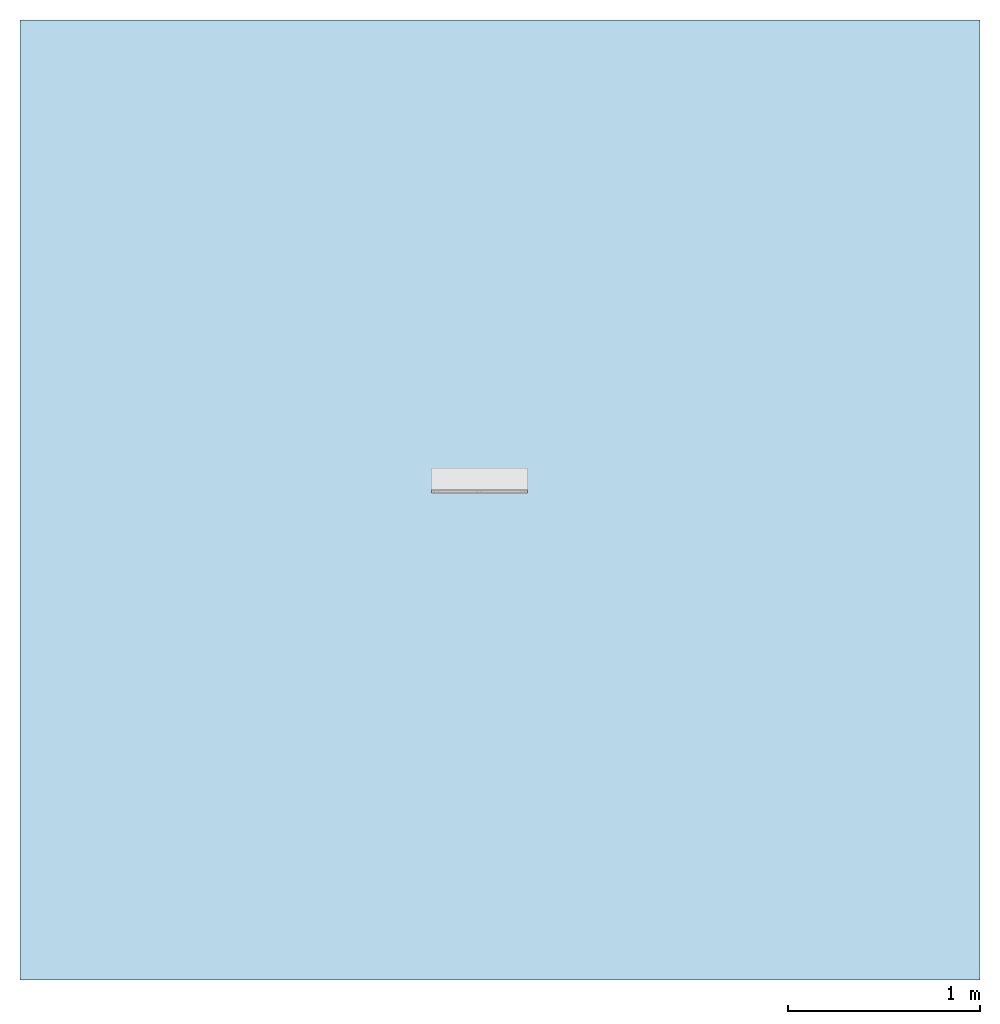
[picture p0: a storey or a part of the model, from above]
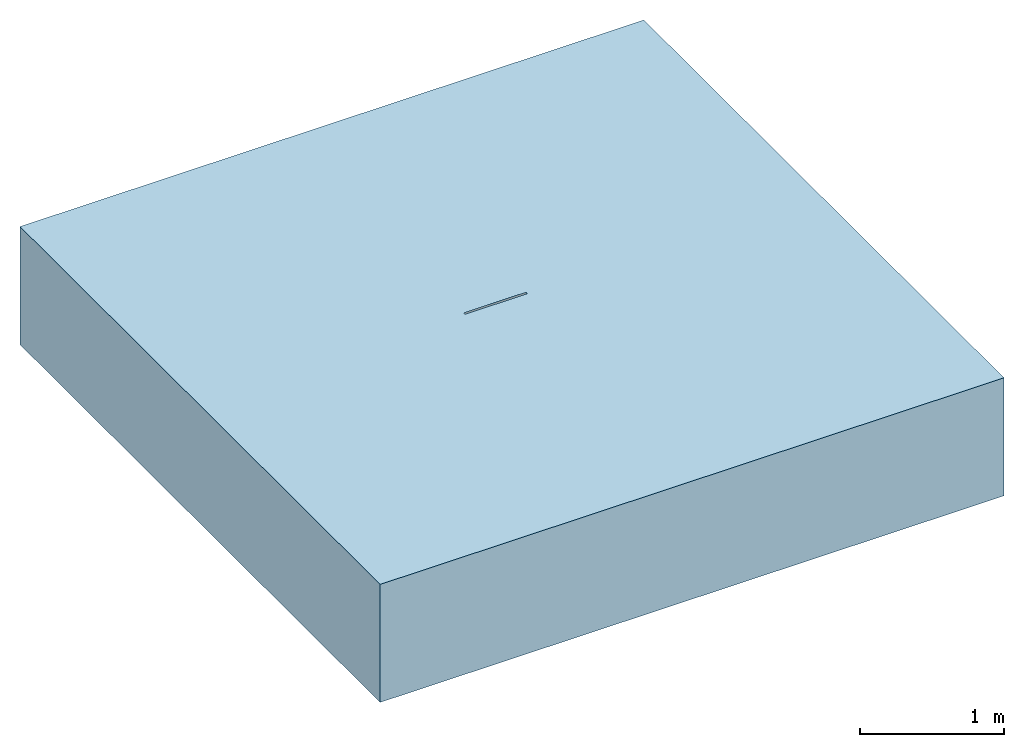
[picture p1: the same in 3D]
Properties of the parts of a building model (IFC2X3)

# File
Description: ViewDefinition [CoordinationView]
File name: 23301 - No 30.1J Constant Depth Channel - 500mm LG - Invert Depth 280mm.ifc
Time: 2013-10-31T17:35:21
Written by: Autodesk Revit 2013
Made in: 20120221_2030(x64)

# IfcProject, Project Number
LongName: Project Name; Phase: Project Status

# IfcSite, Default
RefLatitude: 42, 21, 30, 344238; RefLongitude: -71, -3, -35, -194702; RefElevation: 0 mm

# IfcBuilding
Pset_BuildingCommon - NumberOfStoreys: 1
Other - Client Name: Owner; Project Issue Date: Issue Date; Project Name: Project Name; Project Address: ## Street City, State Zip; Project Status: Project Status; Project Number: Project Number

# IfcBuildingStorey, Level 1
LongName: Level 1; Elevation: 0 mm
Constraints - Elevation Base: 0; Elevation: 0 mm
Graphics - Symbol: M_Level Head - Circle: M_Level Head - Circle; Symbol at End 2 Default: yes; Symbol at End 1 Default: no; Line Pattern: Center; Line Weight: 1; Color: 0
Identity Data - Building Story: yes; Name: Level 1; Structural: no
Dimensions - Computation Height: 0 mm

# IfcBuildingElementProxy: 23301 - No 30.1J Constant Depth Channel - 500mm LG - Invert Depth 280mm, Civil-Drainage-Channel-ACO-MultiDrain-M100D-Brickslot-Channel-System:23301 - No 30.1J Constant Depth Channel - 500mm LG - Invert Depth 280mm:23301 - No 30.1J Constant Depth Channel - 500mm LG - Invert Depth 280mm:196059
In: Level 1
Material: Steel, Galvanized, Vienite® Synthetic Resin Concrete
Construction - 23466_Load Class D400_Brickslot Grating_Galvanized Steel_500mm Long: no; 23460_Load Class C250_Brickslot Grating_Galvanized Steel_1000mm Long: no; 23462_Load Class C250_Brickslot Access Unit_Galvanised Steel_500mm Long: no; 23467_Load Class D400_Brickslot Access Unit_Galvanised Steel_500mm Long: no; 23461_Load Class C250_Brickslot Grating_Galvanized Steel_500mm Long: no; 23465_Load Class D400_Brickslot Grating_Galvanized Steel_1000mm Long: yes; 23404_Universal Endcap (Male End): no; 23404_Universal Endcap (Female End): no; Sloping Channel: no; 23410_Sump Unit: no; Constant Depth Channel: no; Shallow Depth Channel with seal: no; Shallow Depth Channel: no; Constant Depth Junction Channel: yes
Dimensions - Length: 1000 mm; Brickslot Access Unit Void Bottom Depth: -6605 mm; FloorCut_Length: -500 mm; EndCap Position: 500 mm; Brickslot Access Unit Void Depth: -6500 mm; Volume: 6334206 mm3; Custom_Void_length: 500 mm; Brickslot Void Depth: 0 mm; Brickslot Void Length: 500 mm; GratingLength: -1000 mm; ShallowOverallDepth: 75 mm; SlopingEndInvertDepth: 180 mm; SlopingInvertDepth: 175 mm; EndCap_Height: 300 mm; Floor Cut Gap: 105 mm; FloorCut_Depth: 300 mm; Length Drain: -500 mm; SlopingEndOverallDepth: 250 mm; Brickslot Access Unit Floor Cut Length: 500 mm; Depth: 300 mm; FloorCut_Width: 135 mm; Access_Custom_Void_Length: 0 mm; InvDepth: 230 mm; SlopingOverallDepth: 245 mm; ShallowInvDepth: 55 mm
Constraints - Moves With Nearby Elements: no; Level: Level: Level 1
Phasing - Phase Created: New Construction
Pset_BuildingElementProxyCommon - Reference: 23301 - No 30.1J Constant Depth Channel - 500mm LG - Invert Depth 280mm
Identity Data - OmniClass Number: 23.70.50.24; e-mail Sales: customersupport@aco.co.uk; Model: ACO MultiDrain MD Brickslot- M100D; Cost: 0; Assembly Code: D2040; Telephone: +44 (0)1462 816666; URL: www.aco.co.uk; Assembly Description: Rain Water Drainage; Fax: +44 (0)1462 815895; Product Page URL: http://www.aco.co.uk/product_detail.php?id=58; Product brochure: http://www.aco.co.uk/download.php?id=173; OmniClass Title: Rainwater Removal; e-mail Technical: technical@aco.co.uk; Address: ACO Business Park, Hitchin Road, Shefford, Bedfordshire, United Kingdom SG17 5TE; Installation guidelines: http://www.aco.co.uk/download.php?id=173; Model Description: Channel drainage system; Maintenance guidelines: http://www.aco.co.uk/download.php?id=173; Manufacturer: ACO Technologies plc - ACO Water Management Division; Price: POA - contact ACO; Product Code: 23301; Watermark 2: This file is water marked and users are prohibited to reproduce, adapt, distribute this information; Watermarked With: BIM Manager Premium Suite; Type Comments: ACO MultiDrain M100D 30.1J Constant Depth Junction Channel 500mm Long; Watermark 1: This file is the property of ACO Technologies PLC
Data - Concrete Surround Volume - Load Class B 125 - C 250 - Concrete Pavement: 0.16m³/m; Concrete Surround Volume - Load Class A 15 - Concrete Pavement: 0.10m³/m; Channel C.S.A: 0.021m²; Product Standard: BS EN 1433:2002, CE marked; Hydraulic Performance: http://www.aco.co.uk/download.php?id=173; Pre-formed Outlet Ø: N/A; Load Class: A 15 - D 400; Product Dimensions: 500mm x 135mm x 300mm (LxWxH); Concrete Surround Volume - Load Class D 400 - Concrete Pavement: 0.23m³/m; Product Weight: 12.5 Kg; Invert Depth: 280mm; ACO Hydraulic Design Software: http://www.acodesign.co.uk; Installation - Concrete Grade: Refer to brochure
General - SerialNumber: 0; TagNumber: 0
Model Properties - Brickslot Access Unit Product code 23467: Load Class D400 - Brickslot Access Unit Galvanised Steel - 500mm long x 105mm high - 10mm Slot - Intake area - 10000mm²/m - 6.4 Kg; Brickslot Access Unit Product code 23462: Load Class C250 - Brickslot Access Unit Galvanised Steel - 500mm long x 105mm high - 10mm Slot - Intake area - 10000mm²/m - 6.4 Kg; Brickslot Grating Product code 23466: Load Class D400 - Brickslot Galvanised Steel - 500mm long x 105mm high - 10mm Slot - Intake area - 10000mm²/m - 3.3 Kg; Brickslot Grating Product code 23465: N/A; Brickslot Grating Product code 23461: Load Class C250 - Brickslot Galvanised Steel - 500mm long x 105mm high - 10mm Slot - Intake area - 10000mm²/m -3.3 Kg; Brickslot Grating Product code 23460: N/A; End Cap Product code 23404: No 306 Universal End Cap - 135mm wide x 300mm long - Spigot Ø110mm x 50mm long - Silver - Polypropylene - 0.16kg
Green Building Properties - Edge Rail Recyclable: Fully recyclable; Channel Recyclable: Fully recyclable; Edge Rail Recycled Material Content: Between 40% - 90%; Channel Recycled Material Content: 20% minimum
Other - Created By: www.aco.co.uk; Watermarked By: www.aco.co.uk; Revision: 1
Materials and Finishes - Channel Colour: Brown; Edge Rail Material: Steel; Edge Rail Finish: Pre-galvanised; Edge Rail Colour: Silver; Channel Material: Vienite® Synthetic Resin Concrete

# IfcOpeningElement: Recess (2)
In: Level 1
Phasing - Phase Created: New Construction
Constraints - Height Offset From Level: 0 mm; Level: Level: Level 1; Related to Mass: no; Room Bounding: yes
Structural - Structural: no; Enable Analytical Model: no
Dimensions - Thickness: 1000 mm; Volume: 24978805000 mm3; Perimeter: 20000 mm; Area: 25000000 mm2
Graphics - Coarse Scale Fill Color: 0
Construction - Function: 0; Default Thickness: 1000 mm
Analytical Properties - Heat Transfer Coefficient (U): 0.837; Thermal Resistance (R): 1.19474; Roughness: 1; Thermal mass: 1359800; Absorptance: 0.1
Materials and Finishes - Structural Material: Earth

# IfcSlab: Floor:Generic Floor - 1000mm, Floor:Generic Floor - 1000mm:193825
In: Level 1
PredefinedType: FLOOR; Material: Earth 1000 mm
Phasing - Phase Created: New Construction
Constraints - Height Offset From Level: 0 mm; Level: Level: Level 1; Related to Mass: no; Room Bounding: yes
Structural - Structural: no; Enable Analytical Model: no
Dimensions - Thickness: 1000 mm; Volume: 24978805000 mm3; Perimeter: 20000 mm; Area: 25000000 mm2
Pset_SlabCommon - Reference: Generic Floor - 1000mm; IsExternal: no; LoadBearing: yes
Graphics - Coarse Scale Fill Color: 0
Construction - Function: 0; Default Thickness: 1000 mm
Analytical Properties - Heat Transfer Coefficient (U): 0.837; Thermal Resistance (R): 1.19474; Roughness: 1; Thermal mass: 1359800; Absorptance: 0.1
Materials and Finishes - Structural Material: Earth
